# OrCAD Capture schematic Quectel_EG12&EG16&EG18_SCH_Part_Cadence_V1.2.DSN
size A0

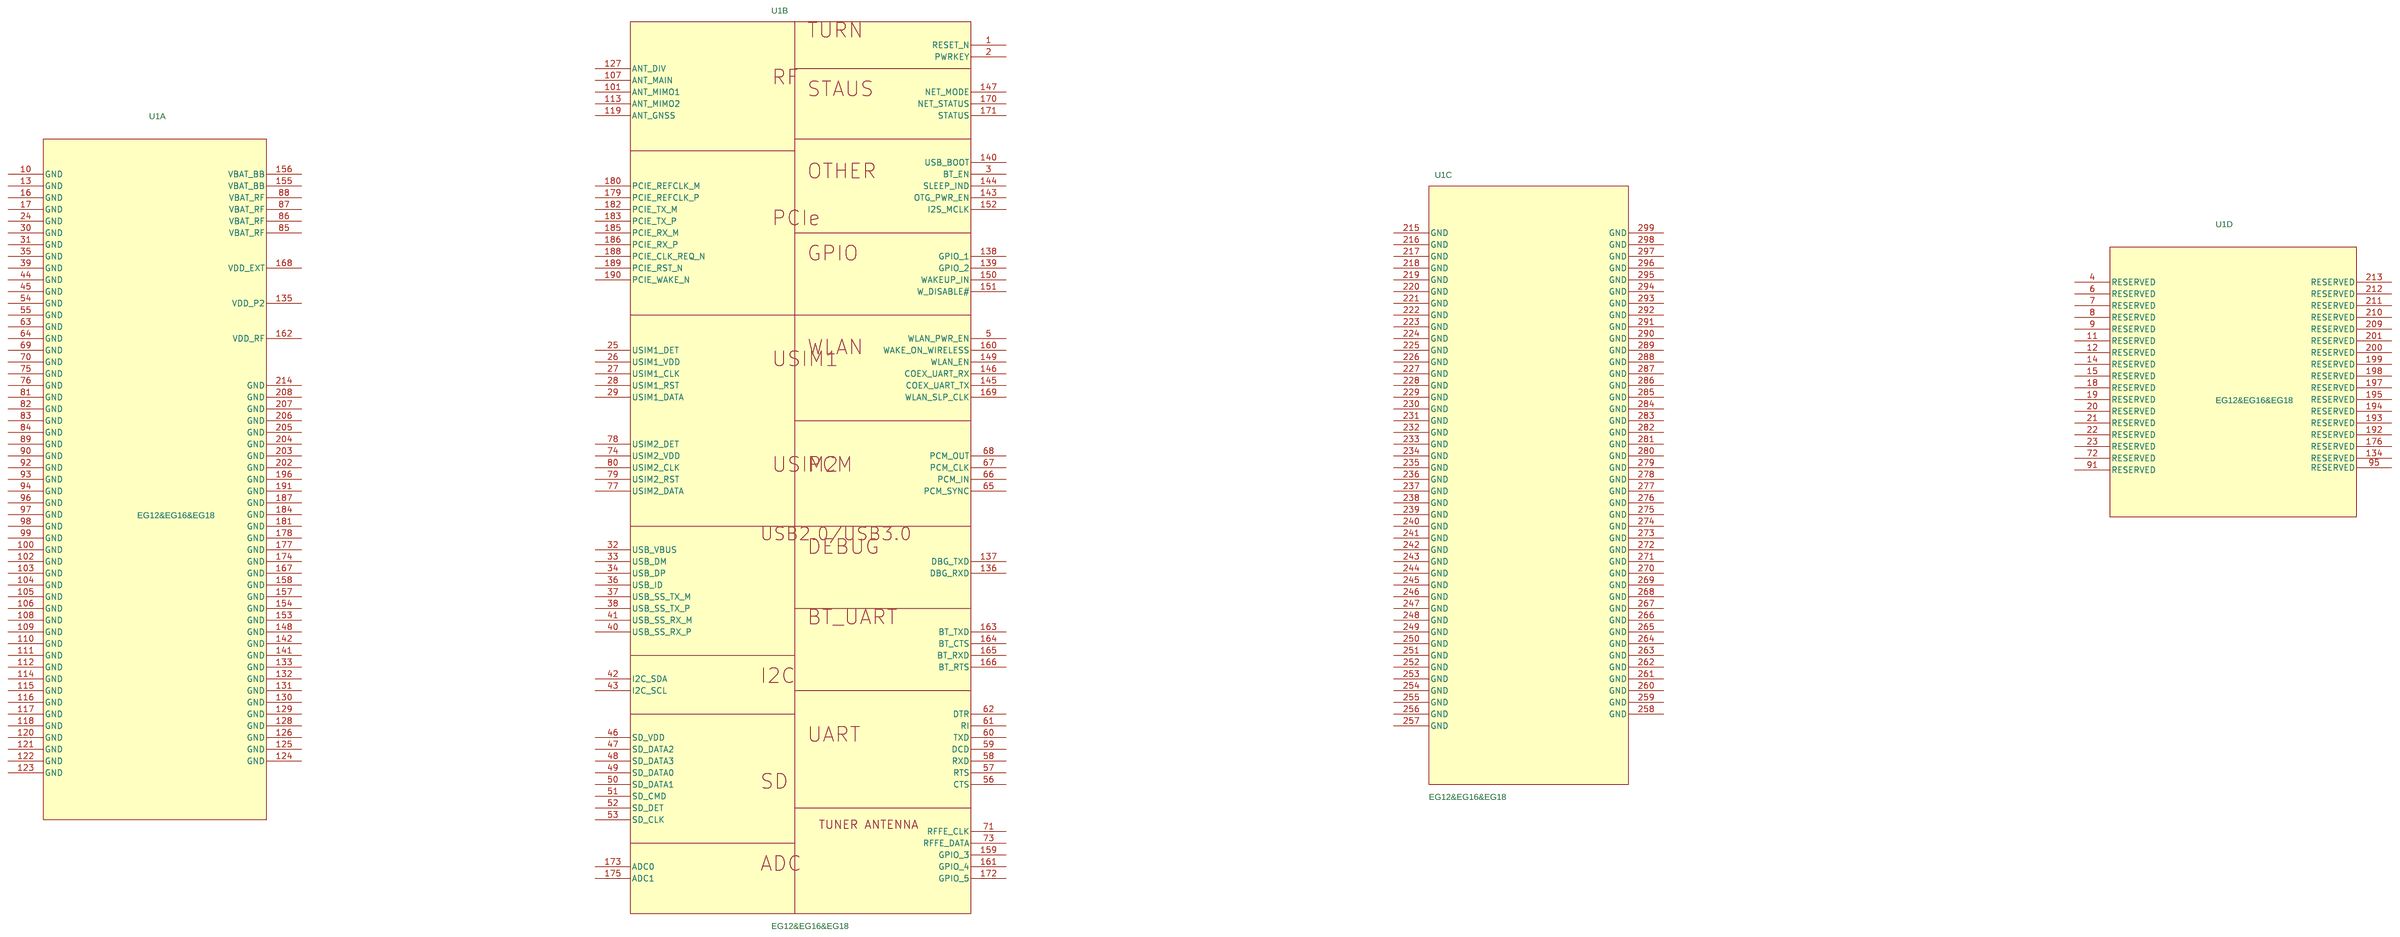
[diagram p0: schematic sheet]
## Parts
U1  EG12&EG16&EG18  (sections A,B,C,D)

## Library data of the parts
U1 = EG12&EG16&EG18

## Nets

Not connected (* = marked no-connect by the designer): U1 1(RESET_N) 2(PWRKEY) 3(BT_EN) 4(RESERVED) 5(WLAN_PWR_EN) 6(RESERVED) 7(RESERVED) 8(RESERVED) 9(RESERVED) 10(GND) 11(RESERVED) 12(RESERVED) 13(GND) 14(RESERVED) 15(RESERVED) 16(GND) 17(GND) 18(RESERVED) 19(RESERVED) 20(RESERVED) 21(RESERVED) 22(RESERVED) 23(RESERVED) 24(GND) 25(USIM1_DET) 26(USIM1_VDD) 27(USIM1_CLK) 28(USIM1_RST) 29(USIM1_DATA) 30(GND) 31(GND) 32(USB_VBUS) 33(USB_DM) 34(USB_DP) 35(GND) 36(USB_ID) 37(USB_SS_TX_M) 38(USB_SS_TX_P) 39(GND) 40(USB_SS_RX_P) 41(USB_SS_RX_M) 42(I2C_SDA) 43(I2C_SCL) 44(GND) 45(GND) 46(SD_VDD) 47(SD_DATA2) 48(SD_DATA3) 49(SD_DATA0) 50(SD_DATA1) 51(SD_CMD) 52(SD_DET) 53(SD_CLK) 54(GND) 55(GND) 56(CTS) 57(RTS) 58(RXD) 59(DCD) 60(TXD) 61(RI) 62(DTR) 63(GND) 64(GND) 65(PCM_SYNC) 66(PCM_IN) 67(PCM_CLK) 68(PCM_OUT) 69(GND) 70(GND) 71(RFFE_CLK) 72(RESERVED) 73(RFFE_DATA) 74(USIM2_VDD) 75(GND) 76(GND) 77(USIM2_DATA) 78(USIM2_DET) 79(USIM2_RST) 80(USIM2_CLK) 81(GND) 82(GND) 83(GND) 84(GND) 85(VBAT_RF) 86(VBAT_RF) 87(VBAT_RF) 88(VBAT_RF) 89(GND) 90(GND) 91(RESERVED) 92(GND) 93(GND) 94(GND) 95(RESERVED) 96(GND) 97(GND) 98(GND) 99(GND) 100(GND) 101(ANT_MIMO1) 102(GND) 103(GND) 104(GND) 105(GND) 106(GND) 107(ANT_MAIN) 108(GND) 109(GND) 110(GND) 111(GND) 112(GND) 113(ANT_MIMO2) 114(GND) 115(GND) 116(GND) 117(GND) 118(GND) 119(ANT_GNSS) 120(GND) 121(GND) 122(GND) 123(GND) 124(GND) 125(GND) 126(GND) 127(ANT_DIV) 128(GND) 129(GND) 130(GND) 131(GND) 132(GND) 133(GND) 134(RESERVED) 135(VDD_P2) 136(DBG_RXD) 137(DBG_TXD) 138(GPIO_1) 139(GPIO_2) 140(USB_BOOT) 141(GND) 142(GND) 143(OTG_PWR_EN) 144(SLEEP_IND) 145(COEX_UART_TX) 146(COEX_UART_RX) 147(NET_MODE) 148(GND) 149(WLAN_EN) 150(WAKEUP_IN) 151(W_DISABLE#) 152(I2S_MCLK) 153(GND) 154(GND) 155(VBAT_BB) 156(VBAT_BB) 157(GND) 158(GND) 159(GPIO_3) 160(WAKE_ON_WIRELESS) 161(GPIO_4) 162(VDD_RF) 163(BT_TXD) 164(BT_CTS) 165(BT_RXD) 166(BT_RTS) 167(GND) 168(VDD_EXT) 169(WLAN_SLP_CLK) 170(NET_STATUS) 171(STATUS) 172(GPIO_5) 173(ADC0) 174(GND) 175(ADC1) 176(RESERVED) 177(GND) 178(GND) 179(PCIE_REFCLK_P) 180(PCIE_REFCLK_M) 181(GND) 182(PCIE_TX_M) 183(PCIE_TX_P) 184(GND) 185(PCIE_RX_M) 186(PCIE_RX_P) 187(GND) 188(PCIE_CLK_REQ_N) 189(PCIE_RST_N) 190(PCIE_WAKE_N) 191(GND) 192(RESERVED) 193(RESERVED) 194(RESERVED) 195(RESERVED) 196(GND) 197(RESERVED) 198(RESERVED) 199(RESERVED) 200(RESERVED) 201(RESERVED) 202(GND) 203(GND) 204(GND) 205(GND) 206(GND) 207(GND) 208(GND) 209(RESERVED) 210(RESERVED) 211(RESERVED) 212(RESERVED) 213(RESERVED) 214(GND) 215(GND) 216(GND) 217(GND) 218(GND) 219(GND) 220(GND) 221(GND) 222(GND) 223(GND) 224(GND) 225(GND) 226(GND) 227(GND) 228(GND) 229(GND) 230(GND) 231(GND) 232(GND) 233(GND) 234(GND) 235(GND) 236(GND) 237(GND) 238(GND) 239(GND) 240(GND) 241(GND) 242(GND) 243(GND) 244(GND) 245(GND) 246(GND) 247(GND) 248(GND) 249(GND) 250(GND) 251(GND) 252(GND) 253(GND) 254(GND) 255(GND) 256(GND) 257(GND) 258(GND) 259(GND) 260(GND) 261(GND) 262(GND) 263(GND) 264(GND) 265(GND) 266(GND) 267(GND) 268(GND) 269(GND) 270(GND) 271(GND) 272(GND) 273(GND) 274(GND) 275(GND) 276(GND) 277(GND) 278(GND) 279(GND) 280(GND) 281(GND) 282(GND) 283(GND) 284(GND) 285(GND) 286(GND) 287(GND) 288(GND) 289(GND) 290(GND) 291(GND) 292(GND) 293(GND) 294(GND) 295(GND) 296(GND) 297(GND) 298(GND) 299(GND)
